One B-rep face of a CAD part: STEP entity #411.
In plain terms, the planar face has unit normal (1, 0, 0).
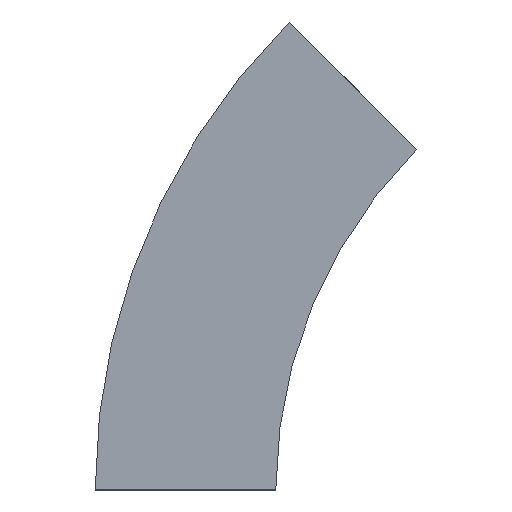
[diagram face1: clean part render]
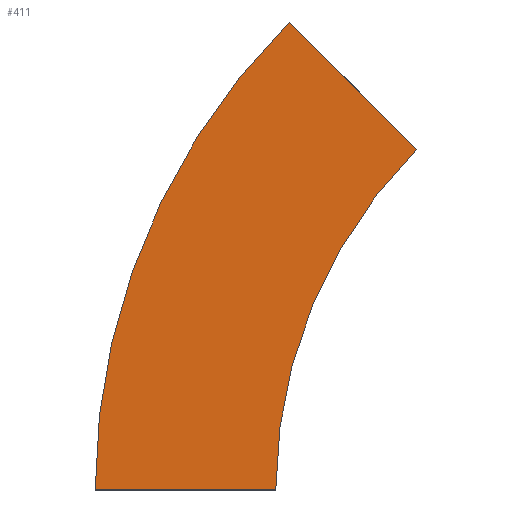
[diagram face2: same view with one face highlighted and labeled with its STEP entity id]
Its self-contained STEP definition (entity closure, numbers rounded to 3 decimals):
#26 = AXIS2_PLACEMENT_3D ( 'NONE', #195, #426, #471 ) ;
#27 = DIRECTION ( 'NONE',  ( 0., 1., 0. ) ) ;
#47 = ORIENTED_EDGE ( 'NONE', *, *, #155, .F. ) ;
#61 = LINE ( 'NONE', #404, #409 ) ;
#97 = DIRECTION ( 'NONE',  ( 0., 1., 0. ) ) ;
#99 = LINE ( 'NONE', #500, #439 ) ;
#130 = DIRECTION ( 'NONE',  ( 1., 0., 0. ) ) ;
#155 = EDGE_CURVE ( 'NONE', #514, #484, #61, .T. ) ;
#161 = CIRCLE ( 'NONE', #251, 300. ) ;
#163 = PLANE ( 'NONE',  #26 ) ;
#188 = DIRECTION ( 'NONE',  ( 0., 0.707, 0.707 ) ) ;
#189 = CIRCLE ( 'NONE', #271, 412.5 ) ;
#195 = CARTESIAN_POINT ( 'NONE',  ( 0., 0., 0. ) ) ;
#200 = FACE_OUTER_BOUND ( 'NONE', #486, .T. ) ;
#211 = CARTESIAN_POINT ( 'NONE',  ( 0., 0., 0. ) ) ;
#213 = VERTEX_POINT ( 'NONE', #485 ) ;
#244 = CARTESIAN_POINT ( 'NONE',  ( 0., -300., 0. ) ) ;
#251 = AXIS2_PLACEMENT_3D ( 'NONE', #563, #130, #481 ) ;
#267 = ORIENTED_EDGE ( 'NONE', *, *, #497, .T. ) ;
#271 = AXIS2_PLACEMENT_3D ( 'NONE', #244, #476, #27 ) ;
#290 = EDGE_CURVE ( 'NONE', #519, #514, #161, .T. ) ;
#306 = ORIENTED_EDGE ( 'NONE', *, *, #373, .T. ) ;
#329 = ORIENTED_EDGE ( 'NONE', *, *, #290, .F. ) ;
#331 = CARTESIAN_POINT ( 'NONE',  ( 0., -87.868, 212.132 ) ) ;
#373 = EDGE_CURVE ( 'NONE', #519, #213, #99, .T. ) ;
#404 = CARTESIAN_POINT ( 'NONE',  ( 0., -87.868, 212.132 ) ) ;
#409 = VECTOR ( 'NONE', #188, 1000. ) ;
#411 = ADVANCED_FACE ( 'NONE', ( #200 ), #163, .T. ) ;
#426 = DIRECTION ( 'NONE',  ( 1., 0., 0. ) ) ;
#439 = VECTOR ( 'NONE', #97, 1000. ) ;
#471 = DIRECTION ( 'NONE',  ( 0., 0., -1. ) ) ;
#476 = DIRECTION ( 'NONE',  ( 1., 0., 0. ) ) ;
#481 = DIRECTION ( 'NONE',  ( 0., 1., 0. ) ) ;
#484 = VERTEX_POINT ( 'NONE', #547 ) ;
#485 = CARTESIAN_POINT ( 'NONE',  ( 0., 112.5, 0. ) ) ;
#486 = EDGE_LOOP ( 'NONE', ( #267, #47, #329, #306 ) ) ;
#497 = EDGE_CURVE ( 'NONE', #213, #484, #189, .T. ) ;
#500 = CARTESIAN_POINT ( 'NONE',  ( 0., 0., 0. ) ) ;
#514 = VERTEX_POINT ( 'NONE', #331 ) ;
#519 = VERTEX_POINT ( 'NONE', #211 ) ;
#547 = CARTESIAN_POINT ( 'NONE',  ( 0., -8.318, 291.682 ) ) ;
#563 = CARTESIAN_POINT ( 'NONE',  ( 0., -300., 0. ) ) ;
